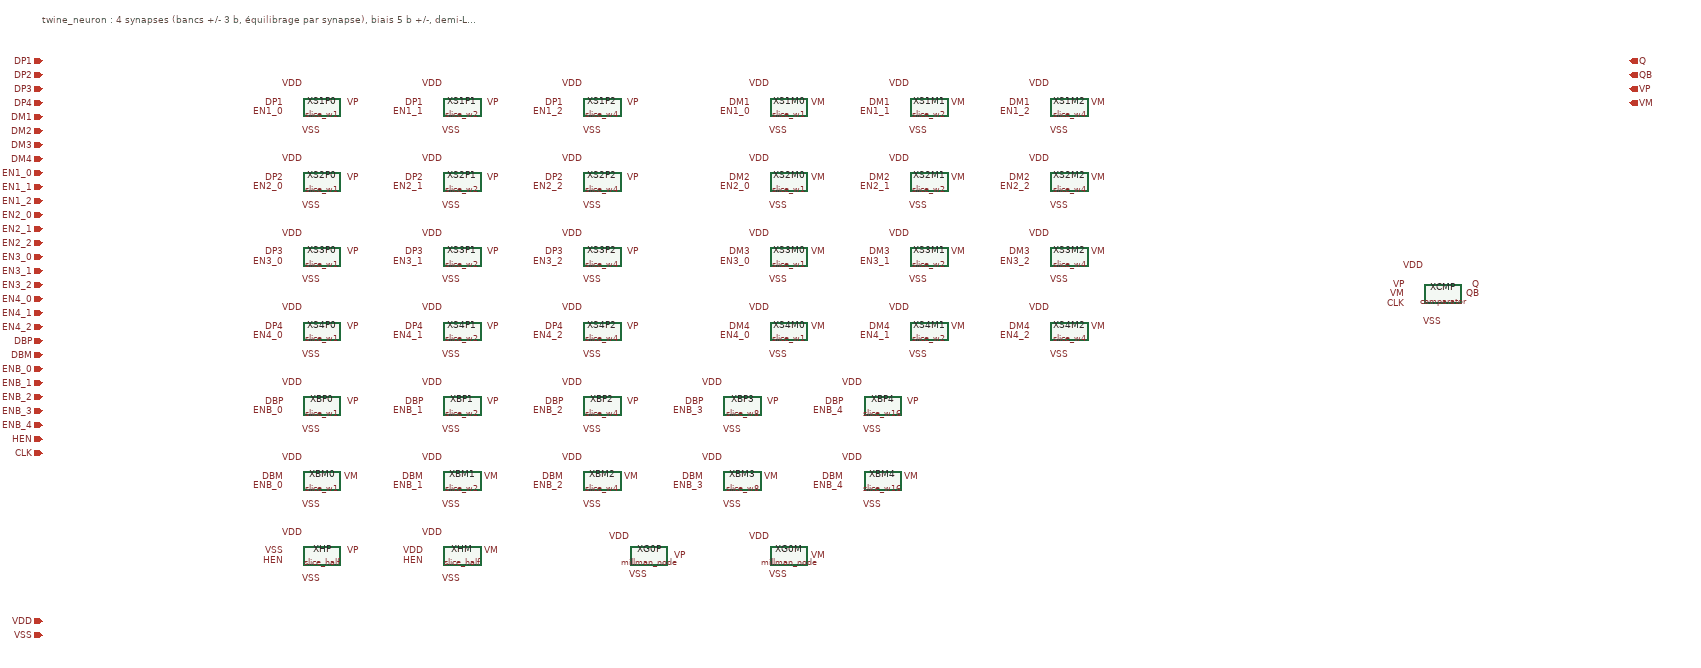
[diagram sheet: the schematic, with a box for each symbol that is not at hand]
v {xschem version=3.4.8RC file_version=1.2}
G {}
K {}
V {}
S {}
E {}
C {ipin.sym} -1600 -800 0 0 {name=p_DP1 lab=DP1}
C {ipin.sym} -1600 -770 0 0 {name=p_DP2 lab=DP2}
C {ipin.sym} -1600 -740 0 0 {name=p_DP3 lab=DP3}
C {ipin.sym} -1600 -710 0 0 {name=p_DP4 lab=DP4}
C {ipin.sym} -1600 -680 0 0 {name=p_DM1 lab=DM1}
C {ipin.sym} -1600 -650 0 0 {name=p_DM2 lab=DM2}
C {ipin.sym} -1600 -620 0 0 {name=p_DM3 lab=DM3}
C {ipin.sym} -1600 -590 0 0 {name=p_DM4 lab=DM4}
C {ipin.sym} -1600 -560 0 0 {name=p_EN1_0 lab=EN1_0}
C {ipin.sym} -1600 -530 0 0 {name=p_EN1_1 lab=EN1_1}
C {ipin.sym} -1600 -500 0 0 {name=p_EN1_2 lab=EN1_2}
C {ipin.sym} -1600 -470 0 0 {name=p_EN2_0 lab=EN2_0}
C {ipin.sym} -1600 -440 0 0 {name=p_EN2_1 lab=EN2_1}
C {ipin.sym} -1600 -410 0 0 {name=p_EN2_2 lab=EN2_2}
C {ipin.sym} -1600 -380 0 0 {name=p_EN3_0 lab=EN3_0}
C {ipin.sym} -1600 -350 0 0 {name=p_EN3_1 lab=EN3_1}
C {ipin.sym} -1600 -320 0 0 {name=p_EN3_2 lab=EN3_2}
C {ipin.sym} -1600 -290 0 0 {name=p_EN4_0 lab=EN4_0}
C {ipin.sym} -1600 -260 0 0 {name=p_EN4_1 lab=EN4_1}
C {ipin.sym} -1600 -230 0 0 {name=p_EN4_2 lab=EN4_2}
C {ipin.sym} -1600 -200 0 0 {name=p_DBP lab=DBP}
C {ipin.sym} -1600 -170 0 0 {name=p_DBM lab=DBM}
C {ipin.sym} -1600 -140 0 0 {name=p_ENB_0 lab=ENB_0}
C {ipin.sym} -1600 -110 0 0 {name=p_ENB_1 lab=ENB_1}
C {ipin.sym} -1600 -80 0 0 {name=p_ENB_2 lab=ENB_2}
C {ipin.sym} -1600 -50 0 0 {name=p_ENB_3 lab=ENB_3}
C {ipin.sym} -1600 -20 0 0 {name=p_ENB_4 lab=ENB_4}
C {ipin.sym} -1600 10 0 0 {name=p_HEN lab=HEN}
C {ipin.sym} -1600 40 0 0 {name=p_CLK lab=CLK}
C {opin.sym} 1800 -800 0 0 {name=p_Q lab=Q}
C {opin.sym} 1800 -770 0 0 {name=p_QB lab=QB}
C {opin.sym} 1800 -740 0 0 {name=p_VP lab=VP}
C {opin.sym} 1800 -710 0 0 {name=p_VM lab=VM}
C {iopin.sym} -1600 400 0 0 {name=p_VDD lab=VDD}
C {iopin.sym} -1600 430 0 0 {name=p_VSS lab=VSS}
C {slice_w1.sym} -1000 -700 0 0 {name=XS1P0}
C {lab_pin.sym} -1080 -710 0 0 {name=l1 sig_type=std_logic lab=DP1}
C {lab_pin.sym} -1080 -690 0 0 {name=l2 sig_type=std_logic lab=EN1_0}
C {lab_pin.sym} -920 -710 0 0 {name=l3 sig_type=std_logic lab=VP}
C {lab_pin.sym} -1040 -750 0 0 {name=l4 sig_type=std_logic lab=VDD}
C {lab_pin.sym} -1000 -650 0 0 {name=l5 sig_type=std_logic lab=VSS}
C {slice_w2.sym} -700 -700 0 0 {name=XS1P1}
C {lab_pin.sym} -780 -710 0 0 {name=l6 sig_type=std_logic lab=DP1}
C {lab_pin.sym} -780 -690 0 0 {name=l7 sig_type=std_logic lab=EN1_1}
C {lab_pin.sym} -620 -710 0 0 {name=l8 sig_type=std_logic lab=VP}
C {lab_pin.sym} -740 -750 0 0 {name=l9 sig_type=std_logic lab=VDD}
C {lab_pin.sym} -700 -650 0 0 {name=l10 sig_type=std_logic lab=VSS}
C {slice_w4.sym} -400 -700 0 0 {name=XS1P2}
C {lab_pin.sym} -480 -710 0 0 {name=l11 sig_type=std_logic lab=DP1}
C {lab_pin.sym} -480 -690 0 0 {name=l12 sig_type=std_logic lab=EN1_2}
C {lab_pin.sym} -320 -710 0 0 {name=l13 sig_type=std_logic lab=VP}
C {lab_pin.sym} -440 -750 0 0 {name=l14 sig_type=std_logic lab=VDD}
C {lab_pin.sym} -400 -650 0 0 {name=l15 sig_type=std_logic lab=VSS}
C {slice_w1.sym} 0 -700 0 0 {name=XS1M0}
C {lab_pin.sym} -80 -710 0 0 {name=l16 sig_type=std_logic lab=DM1}
C {lab_pin.sym} -80 -690 0 0 {name=l17 sig_type=std_logic lab=EN1_0}
C {lab_pin.sym} 80 -710 0 0 {name=l18 sig_type=std_logic lab=VM}
C {lab_pin.sym} -40 -750 0 0 {name=l19 sig_type=std_logic lab=VDD}
C {lab_pin.sym} 0 -650 0 0 {name=l20 sig_type=std_logic lab=VSS}
C {slice_w2.sym} 300 -700 0 0 {name=XS1M1}
C {lab_pin.sym} 220 -710 0 0 {name=l21 sig_type=std_logic lab=DM1}
C {lab_pin.sym} 220 -690 0 0 {name=l22 sig_type=std_logic lab=EN1_1}
C {lab_pin.sym} 380 -710 0 0 {name=l23 sig_type=std_logic lab=VM}
C {lab_pin.sym} 260 -750 0 0 {name=l24 sig_type=std_logic lab=VDD}
C {lab_pin.sym} 300 -650 0 0 {name=l25 sig_type=std_logic lab=VSS}
C {slice_w4.sym} 600 -700 0 0 {name=XS1M2}
C {lab_pin.sym} 520 -710 0 0 {name=l26 sig_type=std_logic lab=DM1}
C {lab_pin.sym} 520 -690 0 0 {name=l27 sig_type=std_logic lab=EN1_2}
C {lab_pin.sym} 680 -710 0 0 {name=l28 sig_type=std_logic lab=VM}
C {lab_pin.sym} 560 -750 0 0 {name=l29 sig_type=std_logic lab=VDD}
C {lab_pin.sym} 600 -650 0 0 {name=l30 sig_type=std_logic lab=VSS}
C {slice_w1.sym} -1000 -540 0 0 {name=XS2P0}
C {lab_pin.sym} -1080 -550 0 0 {name=l31 sig_type=std_logic lab=DP2}
C {lab_pin.sym} -1080 -530 0 0 {name=l32 sig_type=std_logic lab=EN2_0}
C {lab_pin.sym} -920 -550 0 0 {name=l33 sig_type=std_logic lab=VP}
C {lab_pin.sym} -1040 -590 0 0 {name=l34 sig_type=std_logic lab=VDD}
C {lab_pin.sym} -1000 -490 0 0 {name=l35 sig_type=std_logic lab=VSS}
C {slice_w2.sym} -700 -540 0 0 {name=XS2P1}
C {lab_pin.sym} -780 -550 0 0 {name=l36 sig_type=std_logic lab=DP2}
C {lab_pin.sym} -780 -530 0 0 {name=l37 sig_type=std_logic lab=EN2_1}
C {lab_pin.sym} -620 -550 0 0 {name=l38 sig_type=std_logic lab=VP}
C {lab_pin.sym} -740 -590 0 0 {name=l39 sig_type=std_logic lab=VDD}
C {lab_pin.sym} -700 -490 0 0 {name=l40 sig_type=std_logic lab=VSS}
C {slice_w4.sym} -400 -540 0 0 {name=XS2P2}
C {lab_pin.sym} -480 -550 0 0 {name=l41 sig_type=std_logic lab=DP2}
C {lab_pin.sym} -480 -530 0 0 {name=l42 sig_type=std_logic lab=EN2_2}
C {lab_pin.sym} -320 -550 0 0 {name=l43 sig_type=std_logic lab=VP}
C {lab_pin.sym} -440 -590 0 0 {name=l44 sig_type=std_logic lab=VDD}
C {lab_pin.sym} -400 -490 0 0 {name=l45 sig_type=std_logic lab=VSS}
C {slice_w1.sym} 0 -540 0 0 {name=XS2M0}
C {lab_pin.sym} -80 -550 0 0 {name=l46 sig_type=std_logic lab=DM2}
C {lab_pin.sym} -80 -530 0 0 {name=l47 sig_type=std_logic lab=EN2_0}
C {lab_pin.sym} 80 -550 0 0 {name=l48 sig_type=std_logic lab=VM}
C {lab_pin.sym} -40 -590 0 0 {name=l49 sig_type=std_logic lab=VDD}
C {lab_pin.sym} 0 -490 0 0 {name=l50 sig_type=std_logic lab=VSS}
C {slice_w2.sym} 300 -540 0 0 {name=XS2M1}
C {lab_pin.sym} 220 -550 0 0 {name=l51 sig_type=std_logic lab=DM2}
C {lab_pin.sym} 220 -530 0 0 {name=l52 sig_type=std_logic lab=EN2_1}
C {lab_pin.sym} 380 -550 0 0 {name=l53 sig_type=std_logic lab=VM}
C {lab_pin.sym} 260 -590 0 0 {name=l54 sig_type=std_logic lab=VDD}
C {lab_pin.sym} 300 -490 0 0 {name=l55 sig_type=std_logic lab=VSS}
C {slice_w4.sym} 600 -540 0 0 {name=XS2M2}
C {lab_pin.sym} 520 -550 0 0 {name=l56 sig_type=std_logic lab=DM2}
C {lab_pin.sym} 520 -530 0 0 {name=l57 sig_type=std_logic lab=EN2_2}
C {lab_pin.sym} 680 -550 0 0 {name=l58 sig_type=std_logic lab=VM}
C {lab_pin.sym} 560 -590 0 0 {name=l59 sig_type=std_logic lab=VDD}
C {lab_pin.sym} 600 -490 0 0 {name=l60 sig_type=std_logic lab=VSS}
C {slice_w1.sym} -1000 -380 0 0 {name=XS3P0}
C {lab_pin.sym} -1080 -390 0 0 {name=l61 sig_type=std_logic lab=DP3}
C {lab_pin.sym} -1080 -370 0 0 {name=l62 sig_type=std_logic lab=EN3_0}
C {lab_pin.sym} -920 -390 0 0 {name=l63 sig_type=std_logic lab=VP}
C {lab_pin.sym} -1040 -430 0 0 {name=l64 sig_type=std_logic lab=VDD}
C {lab_pin.sym} -1000 -330 0 0 {name=l65 sig_type=std_logic lab=VSS}
C {slice_w2.sym} -700 -380 0 0 {name=XS3P1}
C {lab_pin.sym} -780 -390 0 0 {name=l66 sig_type=std_logic lab=DP3}
C {lab_pin.sym} -780 -370 0 0 {name=l67 sig_type=std_logic lab=EN3_1}
C {lab_pin.sym} -620 -390 0 0 {name=l68 sig_type=std_logic lab=VP}
C {lab_pin.sym} -740 -430 0 0 {name=l69 sig_type=std_logic lab=VDD}
C {lab_pin.sym} -700 -330 0 0 {name=l70 sig_type=std_logic lab=VSS}
C {slice_w4.sym} -400 -380 0 0 {name=XS3P2}
C {lab_pin.sym} -480 -390 0 0 {name=l71 sig_type=std_logic lab=DP3}
C {lab_pin.sym} -480 -370 0 0 {name=l72 sig_type=std_logic lab=EN3_2}
C {lab_pin.sym} -320 -390 0 0 {name=l73 sig_type=std_logic lab=VP}
C {lab_pin.sym} -440 -430 0 0 {name=l74 sig_type=std_logic lab=VDD}
C {lab_pin.sym} -400 -330 0 0 {name=l75 sig_type=std_logic lab=VSS}
C {slice_w1.sym} 0 -380 0 0 {name=XS3M0}
C {lab_pin.sym} -80 -390 0 0 {name=l76 sig_type=std_logic lab=DM3}
C {lab_pin.sym} -80 -370 0 0 {name=l77 sig_type=std_logic lab=EN3_0}
C {lab_pin.sym} 80 -390 0 0 {name=l78 sig_type=std_logic lab=VM}
C {lab_pin.sym} -40 -430 0 0 {name=l79 sig_type=std_logic lab=VDD}
C {lab_pin.sym} 0 -330 0 0 {name=l80 sig_type=std_logic lab=VSS}
C {slice_w2.sym} 300 -380 0 0 {name=XS3M1}
C {lab_pin.sym} 220 -390 0 0 {name=l81 sig_type=std_logic lab=DM3}
C {lab_pin.sym} 220 -370 0 0 {name=l82 sig_type=std_logic lab=EN3_1}
C {lab_pin.sym} 380 -390 0 0 {name=l83 sig_type=std_logic lab=VM}
C {lab_pin.sym} 260 -430 0 0 {name=l84 sig_type=std_logic lab=VDD}
C {lab_pin.sym} 300 -330 0 0 {name=l85 sig_type=std_logic lab=VSS}
C {slice_w4.sym} 600 -380 0 0 {name=XS3M2}
C {lab_pin.sym} 520 -390 0 0 {name=l86 sig_type=std_logic lab=DM3}
C {lab_pin.sym} 520 -370 0 0 {name=l87 sig_type=std_logic lab=EN3_2}
C {lab_pin.sym} 680 -390 0 0 {name=l88 sig_type=std_logic lab=VM}
C {lab_pin.sym} 560 -430 0 0 {name=l89 sig_type=std_logic lab=VDD}
C {lab_pin.sym} 600 -330 0 0 {name=l90 sig_type=std_logic lab=VSS}
C {slice_w1.sym} -1000 -220 0 0 {name=XS4P0}
C {lab_pin.sym} -1080 -230 0 0 {name=l91 sig_type=std_logic lab=DP4}
C {lab_pin.sym} -1080 -210 0 0 {name=l92 sig_type=std_logic lab=EN4_0}
C {lab_pin.sym} -920 -230 0 0 {name=l93 sig_type=std_logic lab=VP}
C {lab_pin.sym} -1040 -270 0 0 {name=l94 sig_type=std_logic lab=VDD}
C {lab_pin.sym} -1000 -170 0 0 {name=l95 sig_type=std_logic lab=VSS}
C {slice_w2.sym} -700 -220 0 0 {name=XS4P1}
C {lab_pin.sym} -780 -230 0 0 {name=l96 sig_type=std_logic lab=DP4}
C {lab_pin.sym} -780 -210 0 0 {name=l97 sig_type=std_logic lab=EN4_1}
C {lab_pin.sym} -620 -230 0 0 {name=l98 sig_type=std_logic lab=VP}
C {lab_pin.sym} -740 -270 0 0 {name=l99 sig_type=std_logic lab=VDD}
C {lab_pin.sym} -700 -170 0 0 {name=l100 sig_type=std_logic lab=VSS}
C {slice_w4.sym} -400 -220 0 0 {name=XS4P2}
C {lab_pin.sym} -480 -230 0 0 {name=l101 sig_type=std_logic lab=DP4}
C {lab_pin.sym} -480 -210 0 0 {name=l102 sig_type=std_logic lab=EN4_2}
C {lab_pin.sym} -320 -230 0 0 {name=l103 sig_type=std_logic lab=VP}
C {lab_pin.sym} -440 -270 0 0 {name=l104 sig_type=std_logic lab=VDD}
C {lab_pin.sym} -400 -170 0 0 {name=l105 sig_type=std_logic lab=VSS}
C {slice_w1.sym} 0 -220 0 0 {name=XS4M0}
C {lab_pin.sym} -80 -230 0 0 {name=l106 sig_type=std_logic lab=DM4}
C {lab_pin.sym} -80 -210 0 0 {name=l107 sig_type=std_logic lab=EN4_0}
C {lab_pin.sym} 80 -230 0 0 {name=l108 sig_type=std_logic lab=VM}
C {lab_pin.sym} -40 -270 0 0 {name=l109 sig_type=std_logic lab=VDD}
C {lab_pin.sym} 0 -170 0 0 {name=l110 sig_type=std_logic lab=VSS}
C {slice_w2.sym} 300 -220 0 0 {name=XS4M1}
C {lab_pin.sym} 220 -230 0 0 {name=l111 sig_type=std_logic lab=DM4}
C {lab_pin.sym} 220 -210 0 0 {name=l112 sig_type=std_logic lab=EN4_1}
C {lab_pin.sym} 380 -230 0 0 {name=l113 sig_type=std_logic lab=VM}
C {lab_pin.sym} 260 -270 0 0 {name=l114 sig_type=std_logic lab=VDD}
C {lab_pin.sym} 300 -170 0 0 {name=l115 sig_type=std_logic lab=VSS}
C {slice_w4.sym} 600 -220 0 0 {name=XS4M2}
C {lab_pin.sym} 520 -230 0 0 {name=l116 sig_type=std_logic lab=DM4}
C {lab_pin.sym} 520 -210 0 0 {name=l117 sig_type=std_logic lab=EN4_2}
C {lab_pin.sym} 680 -230 0 0 {name=l118 sig_type=std_logic lab=VM}
C {lab_pin.sym} 560 -270 0 0 {name=l119 sig_type=std_logic lab=VDD}
C {lab_pin.sym} 600 -170 0 0 {name=l120 sig_type=std_logic lab=VSS}
C {slice_w1.sym} -1000 -60 0 0 {name=XBP0}
C {lab_pin.sym} -1080 -70 0 0 {name=l121 sig_type=std_logic lab=DBP}
C {lab_pin.sym} -1080 -50 0 0 {name=l122 sig_type=std_logic lab=ENB_0}
C {lab_pin.sym} -920 -70 0 0 {name=l123 sig_type=std_logic lab=VP}
C {lab_pin.sym} -1040 -110 0 0 {name=l124 sig_type=std_logic lab=VDD}
C {lab_pin.sym} -1000 -10 0 0 {name=l125 sig_type=std_logic lab=VSS}
C {slice_w2.sym} -700 -60 0 0 {name=XBP1}
C {lab_pin.sym} -780 -70 0 0 {name=l126 sig_type=std_logic lab=DBP}
C {lab_pin.sym} -780 -50 0 0 {name=l127 sig_type=std_logic lab=ENB_1}
C {lab_pin.sym} -620 -70 0 0 {name=l128 sig_type=std_logic lab=VP}
C {lab_pin.sym} -740 -110 0 0 {name=l129 sig_type=std_logic lab=VDD}
C {lab_pin.sym} -700 -10 0 0 {name=l130 sig_type=std_logic lab=VSS}
C {slice_w4.sym} -400 -60 0 0 {name=XBP2}
C {lab_pin.sym} -480 -70 0 0 {name=l131 sig_type=std_logic lab=DBP}
C {lab_pin.sym} -480 -50 0 0 {name=l132 sig_type=std_logic lab=ENB_2}
C {lab_pin.sym} -320 -70 0 0 {name=l133 sig_type=std_logic lab=VP}
C {lab_pin.sym} -440 -110 0 0 {name=l134 sig_type=std_logic lab=VDD}
C {lab_pin.sym} -400 -10 0 0 {name=l135 sig_type=std_logic lab=VSS}
C {slice_w8.sym} -100 -60 0 0 {name=XBP3}
C {lab_pin.sym} -180 -70 0 0 {name=l136 sig_type=std_logic lab=DBP}
C {lab_pin.sym} -180 -50 0 0 {name=l137 sig_type=std_logic lab=ENB_3}
C {lab_pin.sym} -20 -70 0 0 {name=l138 sig_type=std_logic lab=VP}
C {lab_pin.sym} -140 -110 0 0 {name=l139 sig_type=std_logic lab=VDD}
C {lab_pin.sym} -100 -10 0 0 {name=l140 sig_type=std_logic lab=VSS}
C {slice_w16.sym} 200 -60 0 0 {name=XBP4}
C {lab_pin.sym} 120 -70 0 0 {name=l141 sig_type=std_logic lab=DBP}
C {lab_pin.sym} 120 -50 0 0 {name=l142 sig_type=std_logic lab=ENB_4}
C {lab_pin.sym} 280 -70 0 0 {name=l143 sig_type=std_logic lab=VP}
C {lab_pin.sym} 160 -110 0 0 {name=l144 sig_type=std_logic lab=VDD}
C {lab_pin.sym} 200 -10 0 0 {name=l145 sig_type=std_logic lab=VSS}
C {slice_w1.sym} -1000 100 0 0 {name=XBM0}
C {lab_pin.sym} -1080 90 0 0 {name=l146 sig_type=std_logic lab=DBM}
C {lab_pin.sym} -1080 110 0 0 {name=l147 sig_type=std_logic lab=ENB_0}
C {lab_pin.sym} -920 90 0 0 {name=l148 sig_type=std_logic lab=VM}
C {lab_pin.sym} -1040 50 0 0 {name=l149 sig_type=std_logic lab=VDD}
C {lab_pin.sym} -1000 150 0 0 {name=l150 sig_type=std_logic lab=VSS}
C {slice_w2.sym} -700 100 0 0 {name=XBM1}
C {lab_pin.sym} -780 90 0 0 {name=l151 sig_type=std_logic lab=DBM}
C {lab_pin.sym} -780 110 0 0 {name=l152 sig_type=std_logic lab=ENB_1}
C {lab_pin.sym} -620 90 0 0 {name=l153 sig_type=std_logic lab=VM}
C {lab_pin.sym} -740 50 0 0 {name=l154 sig_type=std_logic lab=VDD}
C {lab_pin.sym} -700 150 0 0 {name=l155 sig_type=std_logic lab=VSS}
C {slice_w4.sym} -400 100 0 0 {name=XBM2}
C {lab_pin.sym} -480 90 0 0 {name=l156 sig_type=std_logic lab=DBM}
C {lab_pin.sym} -480 110 0 0 {name=l157 sig_type=std_logic lab=ENB_2}
C {lab_pin.sym} -320 90 0 0 {name=l158 sig_type=std_logic lab=VM}
C {lab_pin.sym} -440 50 0 0 {name=l159 sig_type=std_logic lab=VDD}
C {lab_pin.sym} -400 150 0 0 {name=l160 sig_type=std_logic lab=VSS}
C {slice_w8.sym} -100 100 0 0 {name=XBM3}
C {lab_pin.sym} -180 90 0 0 {name=l161 sig_type=std_logic lab=DBM}
C {lab_pin.sym} -180 110 0 0 {name=l162 sig_type=std_logic lab=ENB_3}
C {lab_pin.sym} -20 90 0 0 {name=l163 sig_type=std_logic lab=VM}
C {lab_pin.sym} -140 50 0 0 {name=l164 sig_type=std_logic lab=VDD}
C {lab_pin.sym} -100 150 0 0 {name=l165 sig_type=std_logic lab=VSS}
C {slice_w16.sym} 200 100 0 0 {name=XBM4}
C {lab_pin.sym} 120 90 0 0 {name=l166 sig_type=std_logic lab=DBM}
C {lab_pin.sym} 120 110 0 0 {name=l167 sig_type=std_logic lab=ENB_4}
C {lab_pin.sym} 280 90 0 0 {name=l168 sig_type=std_logic lab=VM}
C {lab_pin.sym} 160 50 0 0 {name=l169 sig_type=std_logic lab=VDD}
C {lab_pin.sym} 200 150 0 0 {name=l170 sig_type=std_logic lab=VSS}
C {slice_half.sym} -1000 260 0 0 {name=XHP}
C {lab_pin.sym} -1080 250 0 0 {name=l171 sig_type=std_logic lab=VSS}
C {lab_pin.sym} -1080 270 0 0 {name=l172 sig_type=std_logic lab=HEN}
C {lab_pin.sym} -920 250 0 0 {name=l173 sig_type=std_logic lab=VP}
C {lab_pin.sym} -1040 210 0 0 {name=l174 sig_type=std_logic lab=VDD}
C {lab_pin.sym} -1000 310 0 0 {name=l175 sig_type=std_logic lab=VSS}
C {slice_half.sym} -700 260 0 0 {name=XHM}
C {lab_pin.sym} -780 250 0 0 {name=l176 sig_type=std_logic lab=VDD}
C {lab_pin.sym} -780 270 0 0 {name=l177 sig_type=std_logic lab=HEN}
C {lab_pin.sym} -620 250 0 0 {name=l178 sig_type=std_logic lab=VM}
C {lab_pin.sym} -740 210 0 0 {name=l179 sig_type=std_logic lab=VDD}
C {lab_pin.sym} -700 310 0 0 {name=l180 sig_type=std_logic lab=VSS}
C {millman_node.sym} -300 260 0 0 {name=XG0P}
C {lab_pin.sym} -220 260 0 0 {name=l181 sig_type=std_logic lab=VP}
C {lab_pin.sym} -340 220 0 0 {name=l182 sig_type=std_logic lab=VDD}
C {lab_pin.sym} -300 300 0 0 {name=l183 sig_type=std_logic lab=VSS}
C {millman_node.sym} 0 260 0 0 {name=XG0M}
C {lab_pin.sym} 80 260 0 0 {name=l184 sig_type=std_logic lab=VM}
C {lab_pin.sym} -40 220 0 0 {name=l185 sig_type=std_logic lab=VDD}
C {lab_pin.sym} 0 300 0 0 {name=l186 sig_type=std_logic lab=VSS}
C {comparator.sym} 1400 -300 0 0 {name=XCMP}
C {lab_pin.sym} 1320 -320 0 0 {name=l187 sig_type=std_logic lab=VP}
C {lab_pin.sym} 1320 -300 0 0 {name=l188 sig_type=std_logic lab=VM}
C {lab_pin.sym} 1320 -280 0 0 {name=l189 sig_type=std_logic lab=CLK}
C {lab_pin.sym} 1480 -320 0 0 {name=l190 sig_type=std_logic lab=Q}
C {lab_pin.sym} 1480 -300 0 0 {name=l191 sig_type=std_logic lab=QB}
C {lab_pin.sym} 1360 -360 0 0 {name=l192 sig_type=std_logic lab=VDD}
C {lab_pin.sym} 1400 -240 0 0 {name=l193 sig_type=std_logic lab=VSS}
T {twine_neuron : 4 synapses (bancs +/- 3 b, équilibrage par synapse), biais 5 b +/-, demi-LSB, G0 x2, comparateur} -1600 -900 0 0 0.4 0.4 {}
